###############################################################
#  Generated by:      Cadence Innovus 25.11-s102_1
#  OS:                Linux x86_64(Host ID ece-rschsrv.ece.gatech.edu)
#  Generated on:      Fri Oct 10 16:23:34 2025
#  Design:            top_lvl
#  Command:           write_lef_abstract ./output/top_lvl.lef
###############################################################

VERSION 5.8 ;

BUSBITCHARS "[]" ;
DIVIDERCHAR "/" ;

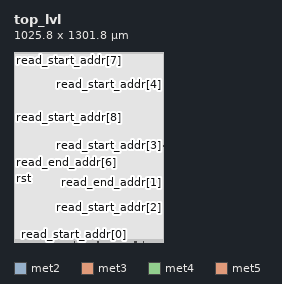
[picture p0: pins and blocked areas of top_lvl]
MACRO top_lvl
  CLASS BLOCK ;
  SIZE 1025.800000 BY 1301.800000 ;
  FOREIGN top_lvl 0.000000 0.000000 ;
  ORIGIN 0 0 ;
  SYMMETRY X Y R90 ;
  PIN clk
    DIRECTION INPUT ;
    USE SIGNAL ;
    ANTENNAPARTIALMETALSIDEAREA 1.568 LAYER met2  ;
    ANTENNAPARTIALMETALAREA 0.3458 LAYER met2  ;
    ANTENNAPARTIALCUTAREA 0.04 LAYER via2  ;
    ANTENNAPARTIALMETALSIDEAREA 2.232 LAYER met3  ;
    ANTENNAPARTIALMETALAREA 0.331 LAYER met3  ;
    ANTENNAPARTIALCUTAREA 0.04 LAYER via3  ;
    ANTENNAPARTIALMETALSIDEAREA 975.24 LAYER met4  ;
    ANTENNAPARTIALMETALAREA 183.543 LAYER met4  ;
    ANTENNAPARTIALCUTAREA 0.64 LAYER via4  ;
    ANTENNAMODEL OXIDE1 ;
    ANTENNAMAXSIDEAREACAR 101.444 LAYER met5  ;
    ANTENNAMAXAREACAR 31.7325 LAYER met5  ;
    ANTENNAPARTIALMETALSIDEAREA 24.144 LAYER met5  ;
    ANTENNAPARTIALMETALAREA 10.976 LAYER met5  ;
    ANTENNAGATEAREA 0.567 LAYER met5  ;
    PORT
      LAYER met2 ;
        RECT 0.000000 10.050000 0.485000 10.190000 ;
    END
  END clk
  PIN rst
    DIRECTION INPUT ;
    USE SIGNAL ;
    ANTENNAMODEL OXIDE1 ;
    ANTENNAMAXSIDEAREACAR 124.719 LAYER met2  ;
    ANTENNAMAXAREACAR 25.5837 LAYER met2  ;
    ANTENNAPARTIALMETALSIDEAREA 217.438 LAYER met2  ;
    ANTENNAPARTIALMETALAREA 43.7387 LAYER met2  ;
    ANTENNAGATEAREA 2.4255 LAYER met2  ;
    ANTENNAPARTIALCUTAREA 0.08 LAYER via2  ;
    ANTENNAMAXCUTCAR 0.17584 LAYER via2  ;
    ANTENNAGATEAREA 2.4255 LAYER via2  ;
    ANTENNAMAXSIDEAREACAR 175.089 LAYER met3  ;
    ANTENNAMAXAREACAR 34.9593 LAYER met3  ;
    ANTENNAPARTIALMETALSIDEAREA 515.664 LAYER met3  ;
    ANTENNAPARTIALMETALAREA 95.9823 LAYER met3  ;
    ANTENNAGATEAREA 10.2375 LAYER met3  ;
    PORT
      LAYER met2 ;
        RECT 0.000000 432.790000 0.485000 432.930000 ;
    END
  END rst
  PIN read_start_addr[8]
    DIRECTION INPUT ;
    USE SIGNAL ;
    ANTENNAMODEL OXIDE1 ;
    ANTENNAMAXSIDEAREACAR 96.2584 LAYER met2  ;
    ANTENNAMAXAREACAR 19.5993 LAYER met2  ;
    ANTENNAPARTIALMETALSIDEAREA 106.327 LAYER met2  ;
    ANTENNAPARTIALMETALAREA 21.3105 LAYER met2  ;
    ANTENNAGATEAREA 1.134 LAYER met2  ;
    PORT
      LAYER met2 ;
        RECT 0.000000 855.990000 0.485000 856.130000 ;
    END
  END read_start_addr[8]
  PIN read_start_addr[7]
    DIRECTION INPUT ;
    USE SIGNAL ;
    ANTENNAPARTIALMETALSIDEAREA 367.374 LAYER met2  ;
    ANTENNAPARTIALMETALAREA 73.5306 LAYER met2  ;
    ANTENNAPARTIALCUTAREA 0.04 LAYER via2  ;
    ANTENNAPARTIALMETALSIDEAREA 1.808 LAYER met3  ;
    ANTENNAPARTIALMETALAREA 0.254 LAYER met3  ;
    ANTENNAPARTIALCUTAREA 0.04 LAYER via3  ;
    ANTENNAMODEL OXIDE1 ;
    ANTENNAMAXSIDEAREACAR 370.81 LAYER met4  ;
    ANTENNAMAXAREACAR 71.7176 LAYER met4  ;
    ANTENNAPARTIALMETALSIDEAREA 63.6 LAYER met4  ;
    ANTENNAPARTIALMETALAREA 11.8368 LAYER met4  ;
    ANTENNAGATEAREA 0.2835 LAYER met4  ;
    PORT
      LAYER met2 ;
        RECT 0.000000 1278.730000 0.485000 1278.870000 ;
    END
  END read_start_addr[7]
  PIN read_start_addr[6]
    DIRECTION INPUT ;
    USE SIGNAL ;
    ANTENNAPARTIALMETALSIDEAREA 418.383 LAYER met2  ;
    ANTENNAPARTIALMETALAREA 83.7796 LAYER met2  ;
    ANTENNAPARTIALCUTAREA 0.04 LAYER via2  ;
    ANTENNAMODEL OXIDE1 ;
    ANTENNAMAXSIDEAREACAR 339.275 LAYER met3  ;
    ANTENNAMAXAREACAR 66.067 LAYER met3  ;
    ANTENNAPARTIALMETALSIDEAREA 60.944 LAYER met3  ;
    ANTENNAPARTIALMETALAREA 11.3388 LAYER met3  ;
    ANTENNAGATEAREA 0.2835 LAYER met3  ;
    PORT
      LAYER met2 ;
        RECT 400.590000 1301.315000 400.730000 1301.800000 ;
    END
  END read_start_addr[6]
  PIN read_start_addr[5]
    DIRECTION INPUT ;
    USE SIGNAL ;
    ANTENNAMODEL OXIDE1 ;
    ANTENNAMAXSIDEAREACAR 155.206 LAYER met2  ;
    ANTENNAMAXAREACAR 32.5397 LAYER met2  ;
    ANTENNAPARTIALMETALSIDEAREA 22.7395 LAYER met2  ;
    ANTENNAPARTIALMETALAREA 4.5695 LAYER met2  ;
    ANTENNAGATEAREA 0.1575 LAYER met2  ;
    PORT
      LAYER met2 ;
        RECT 823.330000 1301.315000 823.470000 1301.800000 ;
    END
  END read_start_addr[5]
  PIN read_start_addr[4]
    DIRECTION INPUT ;
    USE SIGNAL ;
    ANTENNAPARTIALMETALSIDEAREA 105.536 LAYER met2  ;
    ANTENNAPARTIALMETALAREA 21.1393 LAYER met2  ;
    ANTENNAPARTIALCUTAREA 0.04 LAYER via2  ;
    ANTENNAMODEL OXIDE1 ;
    ANTENNAMAXSIDEAREACAR 141.984 LAYER met3  ;
    ANTENNAMAXAREACAR 28.793 LAYER met3  ;
    ANTENNAPARTIALMETALSIDEAREA 5.152 LAYER met3  ;
    ANTENNAPARTIALMETALAREA 0.7896 LAYER met3  ;
    ANTENNAGATEAREA 0.1575 LAYER met3  ;
    PORT
      LAYER met2 ;
        RECT 1025.315000 1080.470000 1025.800000 1080.610000 ;
    END
  END read_start_addr[4]
  PIN read_start_addr[3]
    DIRECTION INPUT ;
    USE SIGNAL ;
    ANTENNAPARTIALMETALSIDEAREA 0.812 LAYER met2  ;
    ANTENNAPARTIALMETALAREA 0.1946 LAYER met2  ;
    ANTENNAPARTIALCUTAREA 0.04 LAYER via2  ;
    ANTENNAMODEL OXIDE1 ;
    ANTENNAMAXSIDEAREACAR 337.464 LAYER met3  ;
    ANTENNAMAXAREACAR 64.6343 LAYER met3  ;
    ANTENNAPARTIALMETALSIDEAREA 50.416 LAYER met3  ;
    ANTENNAPARTIALMETALAREA 9.3648 LAYER met3  ;
    ANTENNAGATEAREA 0.1575 LAYER met3  ;
    PORT
      LAYER met2 ;
        RECT 1025.315000 657.730000 1025.800000 657.870000 ;
    END
  END read_start_addr[3]
  PIN read_start_addr[2]
    DIRECTION INPUT ;
    USE SIGNAL ;
    ANTENNAPARTIALMETALSIDEAREA 121.636 LAYER met2  ;
    ANTENNAPARTIALMETALAREA 24.3593 LAYER met2  ;
    ANTENNAPARTIALCUTAREA 0.04 LAYER via2  ;
    ANTENNAMODEL OXIDE1 ;
    ANTENNAMAXSIDEAREACAR 129.717 LAYER met3  ;
    ANTENNAMAXAREACAR 26.3397 LAYER met3  ;
    ANTENNAPARTIALMETALSIDEAREA 5.152 LAYER met3  ;
    ANTENNAPARTIALMETALAREA 0.7896 LAYER met3  ;
    ANTENNAGATEAREA 0.1575 LAYER met3  ;
    PORT
      LAYER met2 ;
        RECT 1025.315000 234.530000 1025.800000 234.670000 ;
    END
  END read_start_addr[2]
  PIN read_start_addr[1]
    DIRECTION INPUT ;
    USE SIGNAL ;
    ANTENNAMODEL OXIDE1 ;
    ANTENNAMAXSIDEAREACAR 90.2866 LAYER met2  ;
    ANTENNAMAXAREACAR 18.4488 LAYER met2  ;
    ANTENNAPARTIALMETALSIDEAREA 81.4905 LAYER met2  ;
    ANTENNAPARTIALMETALAREA 16.3433 LAYER met2  ;
    ANTENNAGATEAREA 1.134 LAYER met2  ;
    PORT
      LAYER met2 ;
        RECT 837.130000 0.000000 837.270000 0.485000 ;
    END
  END read_start_addr[1]
  PIN read_start_addr[0]
    DIRECTION INPUT ;
    USE SIGNAL ;
    ANTENNAPARTIALMETALSIDEAREA 459.802 LAYER met2  ;
    ANTENNAPARTIALMETALAREA 92.0398 LAYER met2  ;
    ANTENNAPARTIALCUTAREA 0.04 LAYER via2  ;
    ANTENNAPARTIALMETALSIDEAREA 272.168 LAYER met3  ;
    ANTENNAPARTIALMETALAREA 50.944 LAYER met3  ;
    ANTENNAPARTIALCUTAREA 0.04 LAYER via3  ;
    ANTENNAMODEL OXIDE1 ;
    ANTENNAMAXSIDEAREACAR 355.681 LAYER met4  ;
    ANTENNAMAXAREACAR 66.769 LAYER met4  ;
    ANTENNAPARTIALMETALSIDEAREA 22.592 LAYER met4  ;
    ANTENNAPARTIALMETALAREA 4.1478 LAYER met4  ;
    ANTENNAGATEAREA 0.2835 LAYER met4  ;
    PORT
      LAYER met2 ;
        RECT 413.930000 0.000000 414.070000 0.485000 ;
    END
  END read_start_addr[0]
  PIN read_end_addr[8]
    DIRECTION INPUT ;
    USE SIGNAL ;
    ANTENNAPARTIALMETALSIDEAREA 56.126 LAYER met2  ;
    ANTENNAPARTIALMETALAREA 11.2574 LAYER met2  ;
    ANTENNAPARTIALCUTAREA 0.04 LAYER via2  ;
    ANTENNAPARTIALMETALSIDEAREA 289.52 LAYER met3  ;
    ANTENNAPARTIALMETALAREA 54.0211 LAYER met3  ;
    ANTENNAPARTIALCUTAREA 0.04 LAYER via3  ;
    ANTENNAMODEL OXIDE1 ;
    ANTENNAMAXSIDEAREACAR 352.791 LAYER met4  ;
    ANTENNAMAXAREACAR 67.0072 LAYER met4  ;
    ANTENNAPARTIALMETALSIDEAREA 39.552 LAYER met4  ;
    ANTENNAPARTIALMETALAREA 7.0632 LAYER met4  ;
    ANTENNAGATEAREA 0.8505 LAYER met4  ;
    PORT
      LAYER met2 ;
        RECT 0.000000 9.130000 0.485000 9.270000 ;
    END
  END read_end_addr[8]
  PIN read_end_addr[7]
    DIRECTION INPUT ;
    USE SIGNAL ;
    ANTENNAMODEL OXIDE1 ;
    ANTENNAMAXSIDEAREACAR 85.1398 LAYER met3  ;
    ANTENNAMAXAREACAR 16.7402 LAYER met3  ;
    ANTENNAPARTIALMETALSIDEAREA 52.264 LAYER met3  ;
    ANTENNAPARTIALMETALAREA 9.8004 LAYER met3  ;
    ANTENNAGATEAREA 1.134 LAYER met3  ;
    PORT
      LAYER met3 ;
        RECT 0.000000 10.230000 0.800000 10.530000 ;
    END
  END read_end_addr[7]
  PIN read_end_addr[6]
    DIRECTION INPUT ;
    USE SIGNAL ;
    ANTENNAPARTIALMETALSIDEAREA 316.424 LAYER met3  ;
    ANTENNAPARTIALMETALAREA 59.0665 LAYER met3  ;
    ANTENNAPARTIALCUTAREA 0.04 LAYER via3  ;
    ANTENNAMODEL OXIDE1 ;
    ANTENNAMAXSIDEAREACAR 320.409 LAYER met4  ;
    ANTENNAMAXAREACAR 60.1501 LAYER met4  ;
    ANTENNAPARTIALMETALSIDEAREA 29.672 LAYER met4  ;
    ANTENNAPARTIALMETALAREA 5.2989 LAYER met4  ;
    ANTENNAGATEAREA 0.8505 LAYER met4  ;
    PORT
      LAYER met3 ;
        RECT 0.000000 601.320000 0.800000 601.620000 ;
    END
  END read_end_addr[6]
  PIN read_end_addr[5]
    DIRECTION INPUT ;
    USE SIGNAL ;
    ANTENNAPARTIALMETALSIDEAREA 1400.88 LAYER met3  ;
    ANTENNAPARTIALMETALAREA 262.667 LAYER met3  ;
    ANTENNAPARTIALCUTAREA 0.04 LAYER via3  ;
    ANTENNAPARTIALMETALSIDEAREA 766.408 LAYER met4  ;
    ANTENNAPARTIALMETALAREA 144.387 LAYER met4  ;
    ANTENNAPARTIALCUTAREA 0.64 LAYER via4  ;
    ANTENNAMODEL OXIDE1 ;
    ANTENNAMAXSIDEAREACAR 177.15 LAYER met5  ;
    ANTENNAMAXAREACAR 44.4324 LAYER met5  ;
    ANTENNAPARTIALMETALSIDEAREA 27.168 LAYER met5  ;
    ANTENNAPARTIALMETALAREA 12.992 LAYER met5  ;
    ANTENNAGATEAREA 0.8505 LAYER met5  ;
    PORT
      LAYER met3 ;
        RECT 0.000000 1192.410000 0.800000 1192.710000 ;
    END
  END read_end_addr[5]
  PIN read_end_addr[4]
    DIRECTION INPUT ;
    USE SIGNAL ;
    ANTENNAPARTIALMETALSIDEAREA 720.328 LAYER met3  ;
    ANTENNAPARTIALMETALAREA 135.063 LAYER met3  ;
    ANTENNAPARTIALCUTAREA 0.04 LAYER via3  ;
    ANTENNAPARTIALMETALSIDEAREA 970.552 LAYER met4  ;
    ANTENNAPARTIALMETALAREA 182.576 LAYER met4  ;
    ANTENNAPARTIALCUTAREA 0.64 LAYER via4  ;
    ANTENNAMODEL OXIDE1 ;
    ANTENNAMAXSIDEAREACAR 420.186 LAYER met5  ;
    ANTENNAMAXAREACAR 96.5968 LAYER met5  ;
    ANTENNAPARTIALMETALSIDEAREA 38.976 LAYER met5  ;
    ANTENNAPARTIALMETALAREA 20.864 LAYER met5  ;
    ANTENNAGATEAREA 0.8505 LAYER met5  ;
    PORT
      LAYER met3 ;
        RECT 363.710000 1301.000000 364.010000 1301.800000 ;
    END
  END read_end_addr[4]
  PIN read_end_addr[3]
    DIRECTION INPUT ;
    USE SIGNAL ;
    ANTENNAPARTIALMETALSIDEAREA 93.76 LAYER met3  ;
    ANTENNAPARTIALMETALAREA 17.5816 LAYER met3  ;
    ANTENNAPARTIALCUTAREA 0.04 LAYER via3  ;
    ANTENNAPARTIALMETALSIDEAREA 959.64 LAYER met4  ;
    ANTENNAPARTIALMETALAREA 180.618 LAYER met4  ;
    ANTENNAPARTIALCUTAREA 0.64 LAYER via4  ;
    ANTENNAMODEL OXIDE1 ;
    ANTENNAMAXSIDEAREACAR 306.339 LAYER met5  ;
    ANTENNAMAXAREACAR 71.7466 LAYER met5  ;
    ANTENNAPARTIALMETALSIDEAREA 33.072 LAYER met5  ;
    ANTENNAPARTIALMETALAREA 16.928 LAYER met5  ;
    ANTENNAGATEAREA 0.8505 LAYER met5  ;
    PORT
      LAYER met3 ;
        RECT 809.450000 1301.000000 809.750000 1301.800000 ;
    END
  END read_end_addr[3]
  PIN read_end_addr[2]
    DIRECTION INPUT ;
    USE SIGNAL ;
    ANTENNAMODEL OXIDE1 ;
    ANTENNAMAXSIDEAREACAR 567.294 LAYER met3  ;
    ANTENNAMAXAREACAR 111.036 LAYER met3  ;
    ANTENNAPARTIALMETALSIDEAREA 216.152 LAYER met3  ;
    ANTENNAPARTIALMETALAREA 40.5294 LAYER met3  ;
    ANTENNAGATEAREA 0.8505 LAYER met3  ;
    PORT
      LAYER met3 ;
        RECT 1025.000000 996.600000 1025.800000 996.900000 ;
    END
  END read_end_addr[2]
  PIN read_end_addr[1]
    DIRECTION INPUT ;
    USE SIGNAL ;
    ANTENNAMODEL OXIDE1 ;
    ANTENNAMAXSIDEAREACAR 381.83 LAYER met3  ;
    ANTENNAMAXAREACAR 75.6534 LAYER met3  ;
    ANTENNAPARTIALMETALSIDEAREA 48.824 LAYER met3  ;
    ANTENNAPARTIALMETALAREA 9.1554 LAYER met3  ;
    ANTENNAGATEAREA 0.567 LAYER met3  ;
    PORT
      LAYER met3 ;
        RECT 1025.000000 405.510000 1025.800000 405.810000 ;
    END
  END read_end_addr[1]
  PIN read_end_addr[0]
    DIRECTION INPUT ;
    USE SIGNAL ;
    ANTENNAPARTIALMETALSIDEAREA 179.2 LAYER met3  ;
    ANTENNAPARTIALMETALAREA 33.5134 LAYER met3  ;
    ANTENNAPARTIALCUTAREA 0.04 LAYER via3  ;
    ANTENNAPARTIALMETALSIDEAREA 4.08 LAYER met4  ;
    ANTENNAPARTIALMETALAREA 1.4551 LAYER met4  ;
    ANTENNAPARTIALCUTAREA 0.64 LAYER via4  ;
    ANTENNAMODEL OXIDE1 ;
    ANTENNAMAXSIDEAREACAR 225.056 LAYER met5  ;
    ANTENNAMAXAREACAR 116.794 LAYER met5  ;
    ANTENNAPARTIALMETALSIDEAREA 47.532 LAYER met5  ;
    ANTENNAPARTIALMETALAREA 29.128 LAYER met5  ;
    ANTENNAGATEAREA 0.2835 LAYER met5  ;
    PORT
      LAYER met3 ;
        RECT 884.890000 0.000000 885.190000 0.800000 ;
    END
  END read_end_addr[0]
  PIN write_start_addr[8]
    DIRECTION INPUT ;
    USE SIGNAL ;
    ANTENNAPARTIALMETALSIDEAREA 541.112 LAYER met3  ;
    ANTENNAPARTIALMETALAREA 101.372 LAYER met3  ;
    ANTENNAPARTIALCUTAREA 0.04 LAYER via3  ;
    ANTENNAMODEL OXIDE1 ;
    ANTENNAMAXSIDEAREACAR 194.065 LAYER met4  ;
    ANTENNAMAXAREACAR 36.7785 LAYER met4  ;
    ANTENNAPARTIALMETALSIDEAREA 20.64 LAYER met4  ;
    ANTENNAPARTIALMETALAREA 3.7818 LAYER met4  ;
    ANTENNAGATEAREA 0.2835 LAYER met4  ;
    PORT
      LAYER met3 ;
        RECT 439.150000 0.000000 439.450000 0.800000 ;
    END
  END write_start_addr[8]
  PIN write_start_addr[7]
    DIRECTION INPUT ;
    USE SIGNAL ;
    ANTENNAPARTIALMETALSIDEAREA 163.976 LAYER met3  ;
    ANTENNAPARTIALMETALAREA 30.7471 LAYER met3  ;
    ANTENNAPARTIALCUTAREA 0.04 LAYER via3  ;
    ANTENNAMODEL OXIDE1 ;
    ANTENNAMAXSIDEAREACAR 120.824 LAYER met4  ;
    ANTENNAMAXAREACAR 22.3259 LAYER met4  ;
    ANTENNAPARTIALMETALSIDEAREA 6.112 LAYER met4  ;
    ANTENNAPARTIALMETALAREA 0.9696 LAYER met4  ;
    ANTENNAGATEAREA 0.2835 LAYER met4  ;
    PORT
      LAYER met3 ;
        RECT 0.000000 9.620000 0.800000 9.920000 ;
    END
  END write_start_addr[7]
  PIN write_start_addr[6]
    DIRECTION INPUT ;
    USE SIGNAL ;
    ANTENNAPARTIALMETALSIDEAREA 64.632 LAYER met4  ;
    ANTENNAPARTIALMETALAREA 12.8094 LAYER met4  ;
    ANTENNAPARTIALCUTAREA 0.64 LAYER via4  ;
    ANTENNAMODEL OXIDE1 ;
    ANTENNAMAXSIDEAREACAR 273.402 LAYER met5  ;
    ANTENNAMAXAREACAR 130.373 LAYER met5  ;
    ANTENNAPARTIALMETALSIDEAREA 50.484 LAYER met5  ;
    ANTENNAPARTIALMETALAREA 31.096 LAYER met5  ;
    ANTENNAGATEAREA 0.2835 LAYER met5  ;
    PORT
      LAYER met4 ;
        RECT 0.000000 10.230000 0.800000 10.530000 ;
    END
  END write_start_addr[6]
  PIN write_start_addr[5]
    DIRECTION INPUT ;
    USE SIGNAL ;
    ANTENNAPARTIALMETALSIDEAREA 67.232 LAYER met4  ;
    ANTENNAPARTIALMETALAREA 13.2922 LAYER met4  ;
    ANTENNAPARTIALCUTAREA 0.64 LAYER via4  ;
    ANTENNAMODEL OXIDE1 ;
    ANTENNAMAXSIDEAREACAR 351.613 LAYER met5  ;
    ANTENNAMAXAREACAR 129.067 LAYER met5  ;
    ANTENNAPARTIALMETALSIDEAREA 30 LAYER met5  ;
    ANTENNAPARTIALMETALAREA 14.88 LAYER met5  ;
    ANTENNAGATEAREA 0.1575 LAYER met5  ;
    PORT
      LAYER met4 ;
        RECT 0.000000 589.730000 0.800000 590.030000 ;
    END
  END write_start_addr[5]
  PIN write_start_addr[4]
    DIRECTION INPUT ;
    USE SIGNAL ;
    ANTENNAPARTIALMETALSIDEAREA 34.296 LAYER met4  ;
    ANTENNAPARTIALMETALAREA 7.2049 LAYER met4  ;
    ANTENNAPARTIALCUTAREA 0.64 LAYER via4  ;
    ANTENNAMODEL OXIDE1 ;
    ANTENNAMAXSIDEAREACAR 516.66 LAYER met5  ;
    ANTENNAMAXAREACAR 189.848 LAYER met5  ;
    ANTENNAPARTIALMETALSIDEAREA 49.908 LAYER met5  ;
    ANTENNAPARTIALMETALAREA 23.032 LAYER met5  ;
    ANTENNAGATEAREA 0.1575 LAYER met5  ;
    PORT
      LAYER met4 ;
        RECT 0.000000 1169.230000 0.800000 1169.530000 ;
    END
  END write_start_addr[4]
  PIN write_start_addr[3]
    DIRECTION INPUT ;
    USE SIGNAL ;
    ANTENNAMODEL OXIDE1 ;
    ANTENNAMAXSIDEAREACAR 415.617 LAYER met4  ;
    ANTENNAMAXAREACAR 77.0713 LAYER met4  ;
    ANTENNAPARTIALMETALSIDEAREA 96.28 LAYER met4  ;
    ANTENNAPARTIALMETALAREA 17.7006 LAYER met4  ;
    ANTENNAGATEAREA 0.2835 LAYER met4  ;
    PORT
      LAYER met4 ;
        RECT 451.025000 1301.000000 451.325000 1301.800000 ;
    END
  END write_start_addr[3]
  PIN write_start_addr[2]
    DIRECTION INPUT ;
    USE SIGNAL ;
    ANTENNAPARTIALMETALSIDEAREA 213.744 LAYER met4  ;
    ANTENNAPARTIALMETALAREA 40.7632 LAYER met4  ;
    ANTENNAPARTIALCUTAREA 0.64 LAYER via4  ;
    ANTENNAMODEL OXIDE1 ;
    ANTENNAMAXSIDEAREACAR 180.168 LAYER met5  ;
    ANTENNAMAXAREACAR 52.3415 LAYER met5  ;
    ANTENNAPARTIALMETALSIDEAREA 23.784 LAYER met5  ;
    ANTENNAPARTIALMETALAREA 13.296 LAYER met5  ;
    ANTENNAGATEAREA 0.567 LAYER met5  ;
    PORT
      LAYER met4 ;
        RECT 1025.000000 1292.450000 1025.800000 1292.750000 ;
    END
  END write_start_addr[2]
  PIN write_start_addr[1]
    DIRECTION INPUT ;
    USE SIGNAL ;
    ANTENNAMODEL OXIDE1 ;
    ANTENNAMAXSIDEAREACAR 44.4467 LAYER met4  ;
    ANTENNAMAXAREACAR 8.48104 LAYER met4  ;
    ANTENNAPARTIALMETALSIDEAREA 15.536 LAYER met4  ;
    ANTENNAPARTIALMETALAREA 2.8257 LAYER met4  ;
    ANTENNAGATEAREA 1.134 LAYER met4  ;
    PORT
      LAYER met4 ;
        RECT 1025.000000 712.950000 1025.800000 713.250000 ;
    END
  END write_start_addr[1]
  PIN write_start_addr[0]
    DIRECTION INPUT ;
    USE SIGNAL ;
    ANTENNAMODEL OXIDE1 ;
    ANTENNAMAXSIDEAREACAR 302.095 LAYER met4  ;
    ANTENNAMAXAREACAR 56.8465 LAYER met4  ;
    ANTENNAPARTIALMETALSIDEAREA 155.224 LAYER met4  ;
    ANTENNAPARTIALMETALAREA 28.929 LAYER met4  ;
    ANTENNAGATEAREA 0.567 LAYER met4  ;
    PORT
      LAYER met4 ;
        RECT 1025.000000 132.840000 1025.800000 133.140000 ;
    END
  END write_start_addr[0]
  PIN write_end_addr[8]
    DIRECTION INPUT ;
    USE SIGNAL ;
    ANTENNAPARTIALMETALSIDEAREA 225.568 LAYER met4  ;
    ANTENNAPARTIALMETALAREA 43.0684 LAYER met4  ;
    ANTENNAPARTIALCUTAREA 0.64 LAYER via4  ;
    ANTENNAMODEL OXIDE1 ;
    ANTENNAMAXSIDEAREACAR 300.765 LAYER met5  ;
    ANTENNAMAXAREACAR 109.349 LAYER met5  ;
    ANTENNAPARTIALMETALSIDEAREA 88.728 LAYER met5  ;
    ANTENNAPARTIALMETALAREA 43.792 LAYER met5  ;
    ANTENNAGATEAREA 0.567 LAYER met5  ;
    PORT
      LAYER met4 ;
        RECT 575.255000 0.000000 575.555000 0.800000 ;
    END
  END write_end_addr[8]
  PIN write_end_addr[7]
    DIRECTION INPUT ;
    USE SIGNAL ;
    ANTENNAMODEL OXIDE1 ;
    ANTENNAMAXSIDEAREACAR 250.529 LAYER met4  ;
    ANTENNAMAXAREACAR 47.8684 LAYER met4  ;
    ANTENNAPARTIALMETALSIDEAREA 167.56 LAYER met4  ;
    ANTENNAPARTIALMETALAREA 31.4184 LAYER met4  ;
    ANTENNAGATEAREA 0.8505 LAYER met4  ;
    PORT
      LAYER met4 ;
        RECT 0.000000 9.620000 0.800000 9.920000 ;
    END
  END write_end_addr[7]
  PIN write_end_addr[6]
    DIRECTION INPUT ;
    USE SIGNAL ;
    ANTENNAMODEL OXIDE1 ;
    ANTENNAMAXSIDEAREACAR 377.571 LAYER met5  ;
    ANTENNAMAXAREACAR 77.3035 LAYER met5  ;
    ANTENNAPARTIALMETALSIDEAREA 2.736 LAYER met5  ;
    ANTENNAPARTIALMETALAREA 1.824 LAYER met5  ;
    ANTENNAGATEAREA 0.8505 LAYER met5  ;
    PORT
      LAYER met5 ;
        RECT 0.000000 10.800000 2.500000 12.400000 ;
    END
  END write_end_addr[6]
  PIN write_end_addr[5]
    DIRECTION INPUT ;
    USE SIGNAL ;
    ANTENNAMODEL OXIDE1 ;
    ANTENNAMAXSIDEAREACAR 340.486 LAYER met5  ;
    ANTENNAMAXAREACAR 141.384 LAYER met5  ;
    ANTENNAPARTIALMETALSIDEAREA 141.18 LAYER met5  ;
    ANTENNAPARTIALMETALAREA 89 LAYER met5  ;
    ANTENNAGATEAREA 0.8505 LAYER met5  ;
    PORT
      LAYER met5 ;
        RECT 196.995000 1299.300000 198.595000 1301.800000 ;
    END
  END write_end_addr[5]
  PIN write_end_addr[4]
    DIRECTION INPUT ;
    USE SIGNAL ;
    ANTENNAMODEL OXIDE1 ;
    ANTENNAMAXSIDEAREACAR 243.844 LAYER met5  ;
    ANTENNAMAXAREACAR 139.333 LAYER met5  ;
    ANTENNAPARTIALMETALSIDEAREA 168.948 LAYER met5  ;
    ANTENNAPARTIALMETALAREA 107.512 LAYER met5  ;
    ANTENNAGATEAREA 0.8505 LAYER met5  ;
    PORT
      LAYER met5 ;
        RECT 611.505000 1299.300000 613.105000 1301.800000 ;
    END
  END write_end_addr[4]
  PIN write_end_addr[3]
    DIRECTION INPUT ;
    USE SIGNAL ;
    ANTENNAMODEL OXIDE1 ;
    ANTENNAMAXSIDEAREACAR 51.93 LAYER met5  ;
    ANTENNAMAXAREACAR 13.597 LAYER met5  ;
    ANTENNAGATEAREA 0.8505 LAYER met5  ;
    PORT
      LAYER met5 ;
        RECT 1023.300000 1295.460000 1025.800000 1297.060000 ;
    END
  END write_end_addr[3]
  PIN write_end_addr[2]
    DIRECTION INPUT ;
    USE SIGNAL ;
    ANTENNAMODEL OXIDE1 ;
    ANTENNAMAXSIDEAREACAR 485.079 LAYER met5  ;
    ANTENNAMAXAREACAR 97.9249 LAYER met5  ;
    ANTENNAGATEAREA 0.441 LAYER met5  ;
    PORT
      LAYER met5 ;
        RECT 827.985000 0.000000 829.585000 2.500000 ;
    END
  END write_end_addr[2]
  PIN write_end_addr[1]
    DIRECTION INPUT ;
    USE SIGNAL ;
    ANTENNAMODEL OXIDE1 ;
    ANTENNAMAXSIDEAREACAR 327.915 LAYER met5  ;
    ANTENNAMAXAREACAR 206.217 LAYER met5  ;
    ANTENNAPARTIALMETALSIDEAREA 335.292 LAYER met5  ;
    ANTENNAPARTIALMETALAREA 223.528 LAYER met5  ;
    ANTENNAGATEAREA 1.134 LAYER met5  ;
    PORT
      LAYER met5 ;
        RECT 413.475000 0.000000 415.075000 2.500000 ;
    END
  END write_end_addr[1]
  PIN write_end_addr[0]
    DIRECTION INPUT ;
    USE SIGNAL ;
    ANTENNAMODEL OXIDE1 ;
    ANTENNAMAXSIDEAREACAR 290.577 LAYER met5  ;
    ANTENNAMAXAREACAR 64.9169 LAYER met5  ;
    ANTENNAGATEAREA 0.2835 LAYER met5  ;
    PORT
      LAYER met5 ;
        RECT 0.000000 3.480000 2.500000 5.080000 ;
    END
  END write_end_addr[0]
  OBS
    LAYER met1 ;
      RECT 0.000000 0.000000 1025.800000 1301.800000 ;
    LAYER met2 ;
      RECT 823.610000 1301.175000 1025.800000 1301.800000 ;
      RECT 400.870000 1301.175000 823.190000 1301.800000 ;
      RECT 0.000000 1301.175000 400.450000 1301.800000 ;
      RECT 0.000000 1279.010000 1025.800000 1301.175000 ;
      RECT 0.625000 1278.590000 1025.800000 1279.010000 ;
      RECT 0.000000 1080.750000 1025.800000 1278.590000 ;
      RECT 0.000000 1080.330000 1025.175000 1080.750000 ;
      RECT 0.000000 856.270000 1025.800000 1080.330000 ;
      RECT 0.625000 855.850000 1025.800000 856.270000 ;
      RECT 0.000000 658.010000 1025.800000 855.850000 ;
      RECT 0.000000 657.590000 1025.175000 658.010000 ;
      RECT 0.000000 433.070000 1025.800000 657.590000 ;
      RECT 0.625000 432.650000 1025.800000 433.070000 ;
      RECT 0.000000 234.810000 1025.800000 432.650000 ;
      RECT 0.000000 234.390000 1025.175000 234.810000 ;
      RECT 0.000000 10.330000 1025.800000 234.390000 ;
      RECT 0.625000 9.910000 1025.800000 10.330000 ;
      RECT 0.000000 9.410000 1025.800000 9.910000 ;
      RECT 0.625000 8.990000 1025.800000 9.410000 ;
      RECT 0.000000 0.625000 1025.800000 8.990000 ;
      RECT 837.410000 0.000000 1025.800000 0.625000 ;
      RECT 414.210000 0.000000 836.990000 0.625000 ;
      RECT 0.000000 0.000000 413.790000 0.625000 ;
    LAYER met3 ;
      RECT 810.050000 1300.700000 1025.800000 1301.800000 ;
      RECT 364.310000 1300.700000 809.150000 1301.800000 ;
      RECT 0.000000 1300.700000 363.410000 1301.800000 ;
      RECT 0.000000 1193.010000 1025.800000 1300.700000 ;
      RECT 1.100000 1192.110000 1025.800000 1193.010000 ;
      RECT 0.000000 997.200000 1025.800000 1192.110000 ;
      RECT 0.000000 996.300000 1024.700000 997.200000 ;
      RECT 0.000000 601.920000 1025.800000 996.300000 ;
      RECT 1.100000 601.020000 1025.800000 601.920000 ;
      RECT 0.000000 406.110000 1025.800000 601.020000 ;
      RECT 0.000000 405.210000 1024.700000 406.110000 ;
      RECT 0.000000 10.830000 1025.800000 405.210000 ;
      RECT 1.100000 9.320000 1025.800000 10.830000 ;
      RECT 0.000000 1.100000 1025.800000 9.320000 ;
      RECT 885.490000 0.000000 1025.800000 1.100000 ;
      RECT 439.750000 0.000000 884.590000 1.100000 ;
      RECT 0.000000 0.000000 438.850000 1.100000 ;
    LAYER met4 ;
      RECT 451.625000 1300.700000 1025.800000 1301.800000 ;
      RECT 0.000000 1300.700000 450.725000 1301.800000 ;
      RECT 0.000000 1293.050000 1025.800000 1300.700000 ;
      RECT 0.000000 1292.150000 1024.700000 1293.050000 ;
      RECT 0.000000 1169.830000 1025.800000 1292.150000 ;
      RECT 1.100000 1168.930000 1025.800000 1169.830000 ;
      RECT 0.000000 713.550000 1025.800000 1168.930000 ;
      RECT 0.000000 712.650000 1024.700000 713.550000 ;
      RECT 0.000000 590.330000 1025.800000 712.650000 ;
      RECT 1.100000 589.430000 1025.800000 590.330000 ;
      RECT 0.000000 133.440000 1025.800000 589.430000 ;
      RECT 0.000000 132.540000 1024.700000 133.440000 ;
      RECT 0.000000 10.830000 1025.800000 132.540000 ;
      RECT 1.100000 9.320000 1025.800000 10.830000 ;
      RECT 0.000000 1.100000 1025.800000 9.320000 ;
      RECT 575.855000 0.000000 1025.800000 1.100000 ;
      RECT 0.000000 0.000000 574.955000 1.100000 ;
    LAYER met5 ;
      RECT 614.705000 1298.660000 1025.800000 1301.800000 ;
      RECT 614.705000 1297.700000 1021.700000 1298.660000 ;
      RECT 200.195000 1297.700000 609.905000 1301.800000 ;
      RECT 0.000000 1297.700000 195.395000 1301.800000 ;
      RECT 0.000000 1293.860000 1021.700000 1297.700000 ;
      RECT 0.000000 14.000000 1025.800000 1293.860000 ;
      RECT 4.100000 9.200000 1025.800000 14.000000 ;
      RECT 0.000000 6.680000 1025.800000 9.200000 ;
      RECT 4.100000 4.100000 1025.800000 6.680000 ;
      RECT 4.100000 1.880000 411.875000 4.100000 ;
      RECT 831.185000 0.000000 1025.800000 4.100000 ;
      RECT 416.675000 0.000000 826.385000 4.100000 ;
      RECT 0.000000 0.000000 411.875000 1.880000 ;
  END
END top_lvl

END LIBRARY
